VERSION 5.7 ;
  NOWIREEXTENSIONATPIN ON ;
  DIVIDERCHAR "/" ;
  BUSBITCHARS "[]" ;
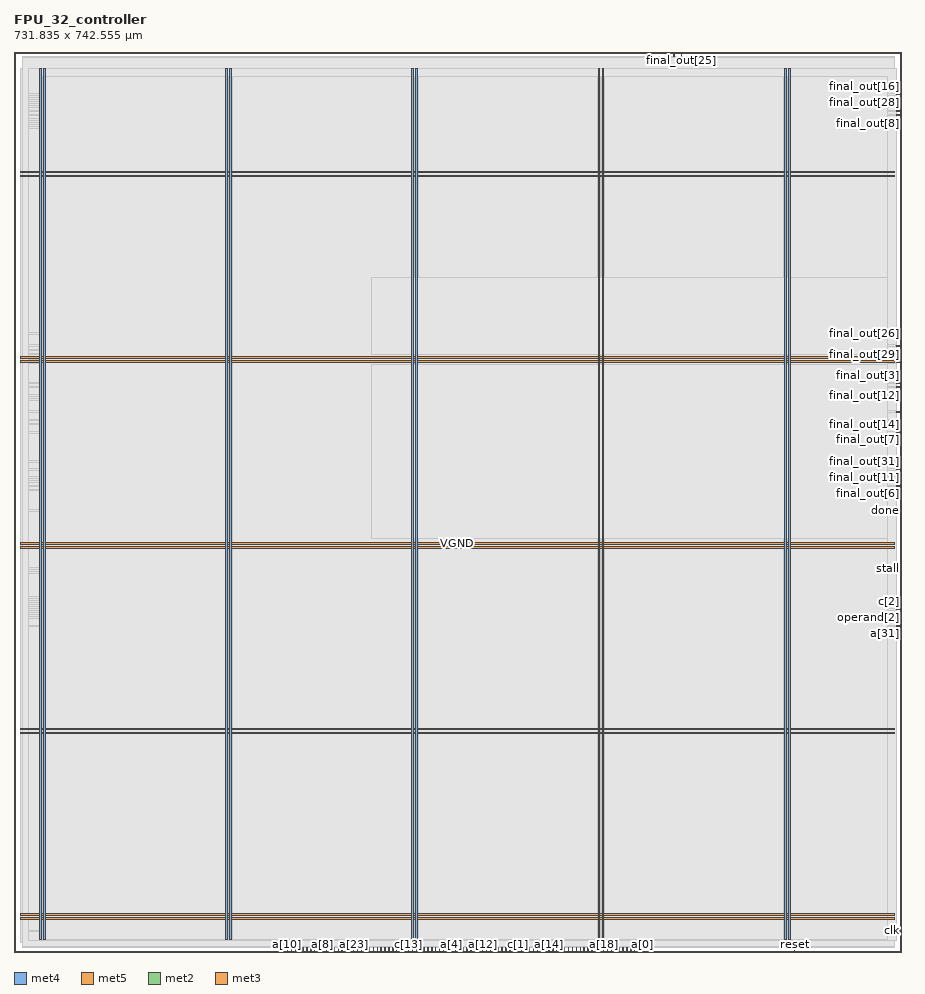
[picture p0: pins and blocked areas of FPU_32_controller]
MACRO FPU_32_controller
  CLASS BLOCK ;
  FOREIGN FPU_32_controller ;
  ORIGIN 0.000 0.000 ;
  SIZE 731.835 BY 742.555 ;
  PIN VGND
    DIRECTION INOUT ;
    USE GROUND ;
    PORT
      LAYER met4 ;
        RECT 24.340 10.640 25.940 729.200 ;
    END
    PORT
      LAYER met4 ;
        RECT 177.940 10.640 179.540 729.200 ;
    END
    PORT
      LAYER met4 ;
        RECT 331.540 10.640 333.140 729.200 ;
    END
    PORT
      LAYER met4 ;
        RECT 485.140 10.640 486.740 729.200 ;
    END
    PORT
      LAYER met4 ;
        RECT 638.740 10.640 640.340 729.200 ;
    END
    PORT
      LAYER met5 ;
        RECT 5.280 30.030 726.120 31.630 ;
    END
    PORT
      LAYER met5 ;
        RECT 5.280 183.210 726.120 184.810 ;
    END
    PORT
      LAYER met5 ;
        RECT 5.280 336.390 726.120 337.990 ;
    END
    PORT
      LAYER met5 ;
        RECT 5.280 489.570 726.120 491.170 ;
    END
    PORT
      LAYER met5 ;
        RECT 5.280 642.750 726.120 644.350 ;
    END
  END VGND
  PIN VPWR
    DIRECTION INOUT ;
    USE POWER ;
    PORT
      LAYER met4 ;
        RECT 21.040 10.640 22.640 729.200 ;
    END
    PORT
      LAYER met4 ;
        RECT 174.640 10.640 176.240 729.200 ;
    END
    PORT
      LAYER met4 ;
        RECT 328.240 10.640 329.840 729.200 ;
    END
    PORT
      LAYER met4 ;
        RECT 481.840 10.640 483.440 729.200 ;
    END
    PORT
      LAYER met4 ;
        RECT 635.440 10.640 637.040 729.200 ;
    END
    PORT
      LAYER met5 ;
        RECT 5.280 26.730 726.120 28.330 ;
    END
    PORT
      LAYER met5 ;
        RECT 5.280 179.910 726.120 181.510 ;
    END
    PORT
      LAYER met5 ;
        RECT 5.280 333.090 726.120 334.690 ;
    END
    PORT
      LAYER met5 ;
        RECT 5.280 486.270 726.120 487.870 ;
    END
    PORT
      LAYER met5 ;
        RECT 5.280 639.450 726.120 641.050 ;
    END
  END VPWR
  PIN a[0]
    DIRECTION INPUT ;
    USE SIGNAL ;
    ANTENNAGATEAREA 0.247500 ;
    PORT
      LAYER met2 ;
        RECT 518.510 0.000 518.790 4.000 ;
    END
  END a[0]
  PIN a[10]
    DIRECTION INPUT ;
    USE SIGNAL ;
    ANTENNAGATEAREA 0.159000 ;
    PORT
      LAYER met2 ;
        RECT 225.490 0.000 225.770 4.000 ;
    END
  END a[10]
  PIN a[11]
    DIRECTION INPUT ;
    USE SIGNAL ;
    ANTENNAGATEAREA 0.159000 ;
    PORT
      LAYER met2 ;
        RECT 228.710 0.000 228.990 4.000 ;
    END
  END a[11]
  PIN a[12]
    DIRECTION INPUT ;
    USE SIGNAL ;
    ANTENNAGATEAREA 0.159000 ;
    PORT
      LAYER met2 ;
        RECT 386.490 0.000 386.770 4.000 ;
    END
  END a[12]
  PIN a[13]
    DIRECTION INPUT ;
    USE SIGNAL ;
    ANTENNAGATEAREA 0.159000 ;
    PORT
      LAYER met2 ;
        RECT 389.710 0.000 389.990 4.000 ;
    END
  END a[13]
  PIN a[14]
    DIRECTION INPUT ;
    USE SIGNAL ;
    ANTENNAGATEAREA 0.213000 ;
    PORT
      LAYER met2 ;
        RECT 441.230 0.000 441.510 4.000 ;
    END
  END a[14]
  PIN a[15]
    DIRECTION INPUT ;
    USE SIGNAL ;
    ANTENNAGATEAREA 0.159000 ;
    PORT
      LAYER met2 ;
        RECT 396.150 0.000 396.430 4.000 ;
    END
  END a[15]
  PIN a[16]
    DIRECTION INPUT ;
    USE SIGNAL ;
    ANTENNAGATEAREA 0.213000 ;
    PORT
      LAYER met2 ;
        RECT 499.190 0.000 499.470 4.000 ;
    END
  END a[16]
  PIN a[17]
    DIRECTION INPUT ;
    USE SIGNAL ;
    ANTENNAGATEAREA 0.213000 ;
    PORT
      LAYER met2 ;
        RECT 508.850 0.000 509.130 4.000 ;
    END
  END a[17]
  PIN a[18]
    DIRECTION INPUT ;
    USE SIGNAL ;
    ANTENNAGATEAREA 0.213000 ;
    PORT
      LAYER met2 ;
        RECT 486.310 0.000 486.590 4.000 ;
    END
  END a[18]
  PIN a[19]
    DIRECTION INPUT ;
    USE SIGNAL ;
    ANTENNAGATEAREA 0.213000 ;
    PORT
      LAYER met2 ;
        RECT 483.090 0.000 483.370 4.000 ;
    END
  END a[19]
  PIN a[1]
    DIRECTION INPUT ;
    USE SIGNAL ;
    ANTENNAGATEAREA 0.213000 ;
    PORT
      LAYER met2 ;
        RECT 402.590 0.000 402.870 4.000 ;
    END
  END a[1]
  PIN a[20]
    DIRECTION INPUT ;
    USE SIGNAL ;
    ANTENNAGATEAREA 0.213000 ;
    PORT
      LAYER met2 ;
        RECT 476.650 0.000 476.930 4.000 ;
    END
  END a[20]
  PIN a[21]
    DIRECTION INPUT ;
    USE SIGNAL ;
    ANTENNAGATEAREA 0.213000 ;
    PORT
      LAYER met2 ;
        RECT 489.530 0.000 489.810 4.000 ;
    END
  END a[21]
  PIN a[22]
    DIRECTION INPUT ;
    USE SIGNAL ;
    ANTENNAGATEAREA 0.213000 ;
    PORT
      LAYER met2 ;
        RECT 470.210 0.000 470.490 4.000 ;
    END
  END a[22]
  PIN a[23]
    DIRECTION INPUT ;
    USE SIGNAL ;
    ANTENNAGATEAREA 0.159000 ;
    PORT
      LAYER met2 ;
        RECT 280.230 0.000 280.510 4.000 ;
    END
  END a[23]
  PIN a[24]
    DIRECTION INPUT ;
    USE SIGNAL ;
    ANTENNAGATEAREA 0.213000 ;
    PORT
      LAYER met2 ;
        RECT 463.770 0.000 464.050 4.000 ;
    END
  END a[24]
  PIN a[25]
    DIRECTION INPUT ;
    USE SIGNAL ;
    ANTENNAGATEAREA 0.213000 ;
    PORT
      LAYER met2 ;
        RECT 357.510 0.000 357.790 4.000 ;
    END
  END a[25]
  PIN a[26]
    DIRECTION INPUT ;
    USE SIGNAL ;
    ANTENNAGATEAREA 0.159000 ;
    PORT
      LAYER met2 ;
        RECT 251.250 0.000 251.530 4.000 ;
    END
  END a[26]
  PIN a[27]
    DIRECTION INPUT ;
    USE SIGNAL ;
    ANTENNAGATEAREA 0.159000 ;
    PORT
      LAYER met2 ;
        RECT 231.930 0.000 232.210 4.000 ;
    END
  END a[27]
  PIN a[28]
    DIRECTION INPUT ;
    USE SIGNAL ;
    ANTENNAGATEAREA 0.213000 ;
    PORT
      LAYER met2 ;
        RECT 460.550 0.000 460.830 4.000 ;
    END
  END a[28]
  PIN a[29]
    DIRECTION INPUT ;
    USE SIGNAL ;
    ANTENNAGATEAREA 0.213000 ;
    PORT
      LAYER met2 ;
        RECT 479.870 0.000 480.150 4.000 ;
    END
  END a[29]
  PIN a[2]
    DIRECTION INPUT ;
    USE SIGNAL ;
    ANTENNAGATEAREA 0.213000 ;
    PORT
      LAYER met2 ;
        RECT 380.050 0.000 380.330 4.000 ;
    END
  END a[2]
  PIN a[30]
    DIRECTION INPUT ;
    USE SIGNAL ;
    ANTENNAGATEAREA 0.213000 ;
    PORT
      LAYER met2 ;
        RECT 392.930 0.000 393.210 4.000 ;
    END
  END a[30]
  PIN a[31]
    DIRECTION INPUT ;
    USE SIGNAL ;
    ANTENNAGATEAREA 0.247500 ;
    PORT
      LAYER met3 ;
        RECT 727.835 268.640 731.835 269.240 ;
    END
  END a[31]
  PIN a[3]
    DIRECTION INPUT ;
    USE SIGNAL ;
    ANTENNAGATEAREA 0.213000 ;
    PORT
      LAYER met2 ;
        RECT 502.410 0.000 502.690 4.000 ;
    END
  END a[3]
  PIN a[4]
    DIRECTION INPUT ;
    USE SIGNAL ;
    ANTENNAGATEAREA 0.159000 ;
    PORT
      LAYER met2 ;
        RECT 360.730 0.000 361.010 4.000 ;
    END
  END a[4]
  PIN a[5]
    DIRECTION INPUT ;
    USE SIGNAL ;
    ANTENNAGATEAREA 0.213000 ;
    PORT
      LAYER met2 ;
        RECT 244.810 0.000 245.090 4.000 ;
    END
  END a[5]
  PIN a[6]
    DIRECTION INPUT ;
    USE SIGNAL ;
    ANTENNAGATEAREA 0.213000 ;
    PORT
      LAYER met2 ;
        RECT 235.150 0.000 235.430 4.000 ;
    END
  END a[6]
  PIN a[7]
    DIRECTION INPUT ;
    USE SIGNAL ;
    ANTENNAGATEAREA 0.213000 ;
    PORT
      LAYER met2 ;
        RECT 248.030 0.000 248.310 4.000 ;
    END
  END a[7]
  PIN a[8]
    DIRECTION INPUT ;
    USE SIGNAL ;
    ANTENNAGATEAREA 0.159000 ;
    PORT
      LAYER met2 ;
        RECT 254.470 0.000 254.750 4.000 ;
    END
  END a[8]
  PIN a[9]
    DIRECTION INPUT ;
    USE SIGNAL ;
    ANTENNAGATEAREA 0.159000 ;
    PORT
      LAYER met2 ;
        RECT 241.590 0.000 241.870 4.000 ;
    END
  END a[9]
  PIN b[0]
    DIRECTION INPUT ;
    USE SIGNAL ;
    ANTENNAGATEAREA 0.213000 ;
    PORT
      LAYER met2 ;
        RECT 457.330 0.000 457.610 4.000 ;
    END
  END b[0]
  PIN b[10]
    DIRECTION INPUT ;
    USE SIGNAL ;
    ANTENNAGATEAREA 0.126000 ;
    PORT
      LAYER met2 ;
        RECT 376.830 0.000 377.110 4.000 ;
    END
  END b[10]
  PIN b[11]
    DIRECTION INPUT ;
    USE SIGNAL ;
    ANTENNAGATEAREA 0.196500 ;
    PORT
      LAYER met2 ;
        RECT 383.270 0.000 383.550 4.000 ;
    END
  END b[11]
  PIN b[12]
    DIRECTION INPUT ;
    USE SIGNAL ;
    ANTENNAGATEAREA 0.159000 ;
    PORT
      LAYER met2 ;
        RECT 505.630 0.000 505.910 4.000 ;
    END
  END b[12]
  PIN b[13]
    DIRECTION INPUT ;
    USE SIGNAL ;
    ANTENNAGATEAREA 0.196500 ;
    PORT
      LAYER met2 ;
        RECT 409.030 0.000 409.310 4.000 ;
    END
  END b[13]
  PIN b[14]
    DIRECTION INPUT ;
    USE SIGNAL ;
    ANTENNAGATEAREA 0.196500 ;
    PORT
      LAYER met2 ;
        RECT 431.570 0.000 431.850 4.000 ;
    END
  END b[14]
  PIN b[15]
    DIRECTION INPUT ;
    USE SIGNAL ;
    ANTENNAGATEAREA 0.213000 ;
    PORT
      LAYER met2 ;
        RECT 428.350 0.000 428.630 4.000 ;
    END
  END b[15]
  PIN b[16]
    DIRECTION INPUT ;
    USE SIGNAL ;
    ANTENNAGATEAREA 0.126000 ;
    PORT
      LAYER met2 ;
        RECT 425.130 0.000 425.410 4.000 ;
    END
  END b[16]
  PIN b[17]
    DIRECTION INPUT ;
    USE SIGNAL ;
    ANTENNAGATEAREA 0.213000 ;
    PORT
      LAYER met2 ;
        RECT 444.450 0.000 444.730 4.000 ;
    END
  END b[17]
  PIN b[18]
    DIRECTION INPUT ;
    USE SIGNAL ;
    ANTENNAGATEAREA 0.159000 ;
    PORT
      LAYER met2 ;
        RECT 515.290 0.000 515.570 4.000 ;
    END
  END b[18]
  PIN b[19]
    DIRECTION INPUT ;
    USE SIGNAL ;
    ANTENNAGATEAREA 0.196500 ;
    PORT
      LAYER met2 ;
        RECT 399.370 0.000 399.650 4.000 ;
    END
  END b[19]
  PIN b[1]
    DIRECTION INPUT ;
    USE SIGNAL ;
    ANTENNAGATEAREA 0.213000 ;
    PORT
      LAYER met2 ;
        RECT 447.670 0.000 447.950 4.000 ;
    END
  END b[1]
  PIN b[20]
    DIRECTION INPUT ;
    USE SIGNAL ;
    ANTENNAGATEAREA 0.159000 ;
    PORT
      LAYER met2 ;
        RECT 466.990 0.000 467.270 4.000 ;
    END
  END b[20]
  PIN b[21]
    DIRECTION INPUT ;
    USE SIGNAL ;
    ANTENNAGATEAREA 0.213000 ;
    PORT
      LAYER met2 ;
        RECT 412.250 0.000 412.530 4.000 ;
    END
  END b[21]
  PIN b[22]
    DIRECTION INPUT ;
    USE SIGNAL ;
    ANTENNAGATEAREA 0.213000 ;
    PORT
      LAYER met2 ;
        RECT 370.390 0.000 370.670 4.000 ;
    END
  END b[22]
  PIN b[23]
    DIRECTION INPUT ;
    USE SIGNAL ;
    ANTENNAGATEAREA 0.126000 ;
    PORT
      LAYER met2 ;
        RECT 363.950 0.000 364.230 4.000 ;
    END
  END b[23]
  PIN b[24]
    DIRECTION INPUT ;
    USE SIGNAL ;
    ANTENNAGATEAREA 0.213000 ;
    PORT
      LAYER met2 ;
        RECT 238.370 0.000 238.650 4.000 ;
    END
  END b[24]
  PIN b[25]
    DIRECTION INPUT ;
    USE SIGNAL ;
    ANTENNAGATEAREA 0.213000 ;
    PORT
      LAYER met2 ;
        RECT 289.890 0.000 290.170 4.000 ;
    END
  END b[25]
  PIN b[26]
    DIRECTION INPUT ;
    USE SIGNAL ;
    ANTENNAGATEAREA 0.213000 ;
    PORT
      LAYER met2 ;
        RECT 347.850 0.000 348.130 4.000 ;
    END
  END b[26]
  PIN b[27]
    DIRECTION INPUT ;
    USE SIGNAL ;
    ANTENNAGATEAREA 0.213000 ;
    PORT
      LAYER met2 ;
        RECT 293.110 0.000 293.390 4.000 ;
    END
  END b[27]
  PIN b[28]
    DIRECTION INPUT ;
    USE SIGNAL ;
    ANTENNAGATEAREA 0.213000 ;
    PORT
      LAYER met2 ;
        RECT 341.410 0.000 341.690 4.000 ;
    END
  END b[28]
  PIN b[29]
    DIRECTION INPUT ;
    USE SIGNAL ;
    ANTENNAGATEAREA 0.213000 ;
    PORT
      LAYER met2 ;
        RECT 315.650 0.000 315.930 4.000 ;
    END
  END b[29]
  PIN b[2]
    DIRECTION INPUT ;
    USE SIGNAL ;
    ANTENNAGATEAREA 0.213000 ;
    PORT
      LAYER met2 ;
        RECT 450.890 0.000 451.170 4.000 ;
    END
  END b[2]
  PIN b[30]
    DIRECTION INPUT ;
    USE SIGNAL ;
    ANTENNAGATEAREA 0.213000 ;
    PORT
      LAYER met2 ;
        RECT 354.290 0.000 354.570 4.000 ;
    END
  END b[30]
  PIN b[31]
    DIRECTION INPUT ;
    USE SIGNAL ;
    ANTENNAGATEAREA 0.213000 ;
    PORT
      LAYER met3 ;
        RECT 727.835 292.440 731.835 293.040 ;
    END
  END b[31]
  PIN b[3]
    DIRECTION INPUT ;
    USE SIGNAL ;
    ANTENNAGATEAREA 0.213000 ;
    PORT
      LAYER met2 ;
        RECT 454.110 0.000 454.390 4.000 ;
    END
  END b[3]
  PIN b[4]
    DIRECTION INPUT ;
    USE SIGNAL ;
    ANTENNAGATEAREA 0.159000 ;
    PORT
      LAYER met2 ;
        RECT 495.970 0.000 496.250 4.000 ;
    END
  END b[4]
  PIN b[5]
    DIRECTION INPUT ;
    USE SIGNAL ;
    ANTENNAGATEAREA 0.213000 ;
    PORT
      LAYER met2 ;
        RECT 492.750 0.000 493.030 4.000 ;
    END
  END b[5]
  PIN b[6]
    DIRECTION INPUT ;
    USE SIGNAL ;
    ANTENNAGATEAREA 0.159000 ;
    PORT
      LAYER met2 ;
        RECT 473.430 0.000 473.710 4.000 ;
    END
  END b[6]
  PIN b[7]
    DIRECTION INPUT ;
    USE SIGNAL ;
    ANTENNAGATEAREA 0.196500 ;
    PORT
      LAYER met2 ;
        RECT 405.810 0.000 406.090 4.000 ;
    END
  END b[7]
  PIN b[8]
    DIRECTION INPUT ;
    USE SIGNAL ;
    ANTENNAGATEAREA 0.126000 ;
    PORT
      LAYER met2 ;
        RECT 367.170 0.000 367.450 4.000 ;
    END
  END b[8]
  PIN b[9]
    DIRECTION INPUT ;
    USE SIGNAL ;
    ANTENNAGATEAREA 0.126000 ;
    PORT
      LAYER met2 ;
        RECT 373.610 0.000 373.890 4.000 ;
    END
  END b[9]
  PIN c[0]
    DIRECTION INPUT ;
    USE SIGNAL ;
    ANTENNAGATEAREA 0.196500 ;
    PORT
      LAYER met2 ;
        RECT 434.790 0.000 435.070 4.000 ;
    END
  END c[0]
  PIN c[10]
    DIRECTION INPUT ;
    USE SIGNAL ;
    ANTENNAGATEAREA 0.196500 ;
    PORT
      LAYER met2 ;
        RECT 344.630 0.000 344.910 4.000 ;
    END
  END c[10]
  PIN c[11]
    DIRECTION INPUT ;
    USE SIGNAL ;
    ANTENNAGATEAREA 0.196500 ;
    PORT
      LAYER met2 ;
        RECT 351.070 0.000 351.350 4.000 ;
    END
  END c[11]
  PIN c[12]
    DIRECTION INPUT ;
    USE SIGNAL ;
    ANTENNAGATEAREA 0.196500 ;
    PORT
      LAYER met2 ;
        RECT 296.330 0.000 296.610 4.000 ;
    END
  END c[12]
  PIN c[13]
    DIRECTION INPUT ;
    USE SIGNAL ;
    ANTENNAGATEAREA 0.196500 ;
    PORT
      LAYER met2 ;
        RECT 325.310 0.000 325.590 4.000 ;
    END
  END c[13]
  PIN c[14]
    DIRECTION INPUT ;
    USE SIGNAL ;
    ANTENNAGATEAREA 0.196500 ;
    PORT
      LAYER met2 ;
        RECT 418.690 0.000 418.970 4.000 ;
    END
  END c[14]
  PIN c[15]
    DIRECTION INPUT ;
    USE SIGNAL ;
    ANTENNAGATEAREA 0.196500 ;
    PORT
      LAYER met2 ;
        RECT 257.690 0.000 257.970 4.000 ;
    END
  END c[15]
  PIN c[16]
    DIRECTION INPUT ;
    USE SIGNAL ;
    ANTENNAGATEAREA 0.196500 ;
    PORT
      LAYER met2 ;
        RECT 421.910 0.000 422.190 4.000 ;
    END
  END c[16]
  PIN c[17]
    DIRECTION INPUT ;
    USE SIGNAL ;
    ANTENNAGATEAREA 0.196500 ;
    PORT
      LAYER met2 ;
        RECT 322.090 0.000 322.370 4.000 ;
    END
  END c[17]
  PIN c[18]
    DIRECTION INPUT ;
    USE SIGNAL ;
    ANTENNAGATEAREA 0.196500 ;
    PORT
      LAYER met2 ;
        RECT 331.750 0.000 332.030 4.000 ;
    END
  END c[18]
  PIN c[19]
    DIRECTION INPUT ;
    USE SIGNAL ;
    ANTENNAGATEAREA 0.196500 ;
    PORT
      LAYER met2 ;
        RECT 260.910 0.000 261.190 4.000 ;
    END
  END c[19]
  PIN c[1]
    DIRECTION INPUT ;
    USE SIGNAL ;
    ANTENNAGATEAREA 0.196500 ;
    PORT
      LAYER met2 ;
        RECT 415.470 0.000 415.750 4.000 ;
    END
  END c[1]
  PIN c[20]
    DIRECTION INPUT ;
    USE SIGNAL ;
    ANTENNAGATEAREA 0.196500 ;
    PORT
      LAYER met2 ;
        RECT 512.070 0.000 512.350 4.000 ;
    END
  END c[20]
  PIN c[21]
    DIRECTION INPUT ;
    USE SIGNAL ;
    ANTENNAGATEAREA 0.196500 ;
    PORT
      LAYER met2 ;
        RECT 299.550 0.000 299.830 4.000 ;
    END
  END c[21]
  PIN c[22]
    DIRECTION INPUT ;
    USE SIGNAL ;
    ANTENNAGATEAREA 0.196500 ;
    PORT
      LAYER met2 ;
        RECT 305.990 0.000 306.270 4.000 ;
    END
  END c[22]
  PIN c[23]
    DIRECTION INPUT ;
    USE SIGNAL ;
    ANTENNAGATEAREA 0.196500 ;
    PORT
      LAYER met2 ;
        RECT 267.350 0.000 267.630 4.000 ;
    END
  END c[23]
  PIN c[24]
    DIRECTION INPUT ;
    USE SIGNAL ;
    ANTENNAGATEAREA 0.196500 ;
    PORT
      LAYER met2 ;
        RECT 273.790 0.000 274.070 4.000 ;
    END
  END c[24]
  PIN c[25]
    DIRECTION INPUT ;
    USE SIGNAL ;
    ANTENNAGATEAREA 0.196500 ;
    PORT
      LAYER met2 ;
        RECT 334.970 0.000 335.250 4.000 ;
    END
  END c[25]
  PIN c[26]
    DIRECTION INPUT ;
    USE SIGNAL ;
    ANTENNAGATEAREA 0.196500 ;
    PORT
      LAYER met2 ;
        RECT 302.770 0.000 303.050 4.000 ;
    END
  END c[26]
  PIN c[27]
    DIRECTION INPUT ;
    USE SIGNAL ;
    ANTENNAGATEAREA 0.196500 ;
    PORT
      LAYER met2 ;
        RECT 312.430 0.000 312.710 4.000 ;
    END
  END c[27]
  PIN c[28]
    DIRECTION INPUT ;
    USE SIGNAL ;
    ANTENNAGATEAREA 0.196500 ;
    PORT
      LAYER met2 ;
        RECT 283.450 0.000 283.730 4.000 ;
    END
  END c[28]
  PIN c[29]
    DIRECTION INPUT ;
    USE SIGNAL ;
    ANTENNAGATEAREA 0.196500 ;
    PORT
      LAYER met2 ;
        RECT 270.570 0.000 270.850 4.000 ;
    END
  END c[29]
  PIN c[2]
    DIRECTION INPUT ;
    USE SIGNAL ;
    ANTENNAGATEAREA 0.213000 ;
    PORT
      LAYER met3 ;
        RECT 727.835 289.040 731.835 289.640 ;
    END
  END c[2]
  PIN c[30]
    DIRECTION INPUT ;
    USE SIGNAL ;
    ANTENNAGATEAREA 0.196500 ;
    PORT
      LAYER met2 ;
        RECT 328.530 0.000 328.810 4.000 ;
    END
  END c[30]
  PIN c[31]
    DIRECTION INPUT ;
    USE SIGNAL ;
    ANTENNAGATEAREA 0.196500 ;
    PORT
      LAYER met2 ;
        RECT 338.190 0.000 338.470 4.000 ;
    END
  END c[31]
  PIN c[3]
    DIRECTION INPUT ;
    USE SIGNAL ;
    ANTENNAGATEAREA 0.196500 ;
    PORT
      LAYER met2 ;
        RECT 438.010 0.000 438.290 4.000 ;
    END
  END c[3]
  PIN c[4]
    DIRECTION INPUT ;
    USE SIGNAL ;
    ANTENNAGATEAREA 0.196500 ;
    PORT
      LAYER met2 ;
        RECT 286.670 0.000 286.950 4.000 ;
    END
  END c[4]
  PIN c[5]
    DIRECTION INPUT ;
    USE SIGNAL ;
    ANTENNAGATEAREA 0.213000 ;
    PORT
      LAYER met3 ;
        RECT 727.835 312.840 731.835 313.440 ;
    END
  END c[5]
  PIN c[6]
    DIRECTION INPUT ;
    USE SIGNAL ;
    ANTENNAGATEAREA 0.196500 ;
    PORT
      LAYER met2 ;
        RECT 264.130 0.000 264.410 4.000 ;
    END
  END c[6]
  PIN c[7]
    DIRECTION INPUT ;
    USE SIGNAL ;
    ANTENNAGATEAREA 0.196500 ;
    PORT
      LAYER met2 ;
        RECT 309.210 0.000 309.490 4.000 ;
    END
  END c[7]
  PIN c[8]
    DIRECTION INPUT ;
    USE SIGNAL ;
    ANTENNAGATEAREA 0.196500 ;
    PORT
      LAYER met2 ;
        RECT 318.870 0.000 319.150 4.000 ;
    END
  END c[8]
  PIN c[9]
    DIRECTION INPUT ;
    USE SIGNAL ;
    ANTENNAGATEAREA 0.196500 ;
    PORT
      LAYER met2 ;
        RECT 277.010 0.000 277.290 4.000 ;
    END
  END c[9]
  PIN clk
    DIRECTION INPUT ;
    USE SIGNAL ;
    ANTENNAGATEAREA 1.286700 ;
    ANTENNADIFFAREA 0.434700 ;
    PORT
      LAYER met3 ;
        RECT 727.835 17.040 731.835 17.640 ;
    END
  END clk
  PIN done
    DIRECTION OUTPUT ;
    USE SIGNAL ;
    ANTENNADIFFAREA 0.445500 ;
    PORT
      LAYER met3 ;
        RECT 727.835 363.840 731.835 364.440 ;
    END
  END done
  PIN final_out[0]
    DIRECTION OUTPUT ;
    USE SIGNAL ;
    ANTENNADIFFAREA 0.445500 ;
    PORT
      LAYER met3 ;
        RECT 727.835 380.840 731.835 381.440 ;
    END
  END final_out[0]
  PIN final_out[10]
    DIRECTION OUTPUT ;
    USE SIGNAL ;
    ANTENNADIFFAREA 0.445500 ;
    PORT
      LAYER met3 ;
        RECT 727.835 489.640 731.835 490.240 ;
    END
  END final_out[10]
  PIN final_out[11]
    DIRECTION OUTPUT ;
    USE SIGNAL ;
    ANTENNADIFFAREA 0.445500 ;
    PORT
      LAYER met3 ;
        RECT 727.835 391.040 731.835 391.640 ;
    END
  END final_out[11]
  PIN final_out[12]
    DIRECTION OUTPUT ;
    USE SIGNAL ;
    ANTENNADIFFAREA 0.445500 ;
    PORT
      LAYER met3 ;
        RECT 727.835 459.040 731.835 459.640 ;
    END
  END final_out[12]
  PIN final_out[13]
    DIRECTION OUTPUT ;
    USE SIGNAL ;
    ANTENNADIFFAREA 0.445500 ;
    PORT
      LAYER met3 ;
        RECT 727.835 455.640 731.835 456.240 ;
    END
  END final_out[13]
  PIN final_out[14]
    DIRECTION OUTPUT ;
    USE SIGNAL ;
    ANTENNADIFFAREA 0.445500 ;
    PORT
      LAYER met3 ;
        RECT 727.835 435.240 731.835 435.840 ;
    END
  END final_out[14]
  PIN final_out[15]
    DIRECTION OUTPUT ;
    USE SIGNAL ;
    ANTENNADIFFAREA 0.445500 ;
    PORT
      LAYER met3 ;
        RECT 727.835 496.440 731.835 497.040 ;
    END
  END final_out[15]
  PIN final_out[16]
    DIRECTION OUTPUT ;
    USE SIGNAL ;
    ANTENNADIFFAREA 0.445500 ;
    PORT
      LAYER met3 ;
        RECT 727.835 707.240 731.835 707.840 ;
    END
  END final_out[16]
  PIN final_out[17]
    DIRECTION OUTPUT ;
    USE SIGNAL ;
    ANTENNADIFFAREA 0.445500 ;
    PORT
      LAYER met3 ;
        RECT 727.835 693.640 731.835 694.240 ;
    END
  END final_out[17]
  PIN final_out[18]
    DIRECTION OUTPUT ;
    USE SIGNAL ;
    ANTENNADIFFAREA 0.445500 ;
    PORT
      LAYER met3 ;
        RECT 727.835 680.040 731.835 680.640 ;
    END
  END final_out[18]
  PIN final_out[19]
    DIRECTION OUTPUT ;
    USE SIGNAL ;
    ANTENNADIFFAREA 0.445500 ;
    PORT
      LAYER met3 ;
        RECT 727.835 690.240 731.835 690.840 ;
    END
  END final_out[19]
  PIN final_out[1]
    DIRECTION OUTPUT ;
    USE SIGNAL ;
    ANTENNADIFFAREA 0.445500 ;
    PORT
      LAYER met3 ;
        RECT 727.835 387.640 731.835 388.240 ;
    END
  END final_out[1]
  PIN final_out[20]
    DIRECTION OUTPUT ;
    USE SIGNAL ;
    ANTENNADIFFAREA 0.445500 ;
    PORT
      LAYER met3 ;
        RECT 727.835 697.040 731.835 697.640 ;
    END
  END final_out[20]
  PIN final_out[21]
    DIRECTION OUTPUT ;
    USE SIGNAL ;
    ANTENNADIFFAREA 0.445500 ;
    PORT
      LAYER met3 ;
        RECT 727.835 703.840 731.835 704.440 ;
    END
  END final_out[21]
  PIN final_out[22]
    DIRECTION OUTPUT ;
    USE SIGNAL ;
    ANTENNADIFFAREA 0.445500 ;
    PORT
      LAYER met3 ;
        RECT 727.835 686.840 731.835 687.440 ;
    END
  END final_out[22]
  PIN final_out[23]
    DIRECTION OUTPUT ;
    USE SIGNAL ;
    ANTENNADIFFAREA 0.445500 ;
    PORT
      LAYER met3 ;
        RECT 727.835 445.440 731.835 446.040 ;
    END
  END final_out[23]
  PIN final_out[24]
    DIRECTION OUTPUT ;
    USE SIGNAL ;
    ANTENNADIFFAREA 0.445500 ;
    PORT
      LAYER met2 ;
        RECT 541.050 738.555 541.330 742.555 ;
    END
  END final_out[24]
  PIN final_out[25]
    DIRECTION OUTPUT ;
    USE SIGNAL ;
    ANTENNADIFFAREA 0.445500 ;
    PORT
      LAYER met2 ;
        RECT 550.710 738.555 550.990 742.555 ;
    END
  END final_out[25]
  PIN final_out[26]
    DIRECTION OUTPUT ;
    USE SIGNAL ;
    ANTENNADIFFAREA 0.445500 ;
    PORT
      LAYER met3 ;
        RECT 727.835 510.040 731.835 510.640 ;
    END
  END final_out[26]
  PIN final_out[27]
    DIRECTION OUTPUT ;
    USE SIGNAL ;
    ANTENNADIFFAREA 0.445500 ;
    PORT
      LAYER met2 ;
        RECT 544.270 738.555 544.550 742.555 ;
    END
  END final_out[27]
  PIN final_out[28]
    DIRECTION OUTPUT ;
    USE SIGNAL ;
    ANTENNADIFFAREA 0.445500 ;
    PORT
      LAYER met3 ;
        RECT 727.835 700.440 731.835 701.040 ;
    END
  END final_out[28]
  PIN final_out[29]
    DIRECTION OUTPUT ;
    USE SIGNAL ;
    ANTENNADIFFAREA 0.445500 ;
    PORT
      LAYER met3 ;
        RECT 727.835 493.040 731.835 493.640 ;
    END
  END final_out[29]
  PIN final_out[2]
    DIRECTION OUTPUT ;
    USE SIGNAL ;
    ANTENNADIFFAREA 0.445500 ;
    PORT
      LAYER met3 ;
        RECT 727.835 438.640 731.835 439.240 ;
    END
  END final_out[2]
  PIN final_out[30]
    DIRECTION OUTPUT ;
    USE SIGNAL ;
    ANTENNADIFFAREA 0.445500 ;
    PORT
      LAYER met3 ;
        RECT 727.835 465.840 731.835 466.440 ;
    END
  END final_out[30]
  PIN final_out[31]
    DIRECTION OUTPUT ;
    USE SIGNAL ;
    ANTENNADIFFAREA 0.445500 ;
    PORT
      LAYER met3 ;
        RECT 727.835 404.640 731.835 405.240 ;
    END
  END final_out[31]
  PIN final_out[3]
    DIRECTION OUTPUT ;
    USE SIGNAL ;
    ANTENNADIFFAREA 0.445500 ;
    PORT
      LAYER met3 ;
        RECT 727.835 469.240 731.835 469.840 ;
    END
  END final_out[3]
  PIN final_out[4]
    DIRECTION OUTPUT ;
    USE SIGNAL ;
    ANTENNADIFFAREA 0.445500 ;
    PORT
      LAYER met3 ;
        RECT 727.835 499.840 731.835 500.440 ;
    END
  END final_out[4]
  PIN final_out[5]
    DIRECTION OUTPUT ;
    USE SIGNAL ;
    ANTENNADIFFAREA 0.445500 ;
    PORT
      LAYER met3 ;
        RECT 727.835 397.840 731.835 398.440 ;
    END
  END final_out[5]
  PIN final_out[6]
    DIRECTION OUTPUT ;
    USE SIGNAL ;
    ANTENNADIFFAREA 0.445500 ;
    PORT
      LAYER met3 ;
        RECT 727.835 384.240 731.835 384.840 ;
    END
  END final_out[6]
  PIN final_out[7]
    DIRECTION OUTPUT ;
    USE SIGNAL ;
    ANTENNADIFFAREA 0.445500 ;
    PORT
      LAYER met3 ;
        RECT 727.835 428.440 731.835 429.040 ;
    END
  END final_out[7]
  PIN final_out[8]
    DIRECTION OUTPUT ;
    USE SIGNAL ;
    ANTENNADIFFAREA 0.445500 ;
    PORT
      LAYER met3 ;
        RECT 727.835 683.440 731.835 684.040 ;
    END
  END final_out[8]
  PIN final_out[9]
    DIRECTION OUTPUT ;
    USE SIGNAL ;
    ANTENNADIFFAREA 0.445500 ;
    PORT
      LAYER met3 ;
        RECT 727.835 486.240 731.835 486.840 ;
    END
  END final_out[9]
  PIN operand[0]
    DIRECTION INPUT ;
    USE SIGNAL ;
    ANTENNAGATEAREA 0.247500 ;
    PORT
      LAYER met3 ;
        RECT 727.835 275.440 731.835 276.040 ;
    END
  END operand[0]
  PIN operand[1]
    DIRECTION INPUT ;
    USE SIGNAL ;
    ANTENNAGATEAREA 0.247500 ;
    PORT
      LAYER met3 ;
        RECT 727.835 278.840 731.835 279.440 ;
    END
  END operand[1]
  PIN operand[2]
    DIRECTION INPUT ;
    USE SIGNAL ;
    ANTENNAGATEAREA 0.247500 ;
    PORT
      LAYER met3 ;
        RECT 727.835 282.240 731.835 282.840 ;
    END
  END operand[2]
  PIN operand[3]
    DIRECTION INPUT ;
    USE SIGNAL ;
    ANTENNAGATEAREA 0.426000 ;
    PORT
      LAYER met3 ;
        RECT 727.835 285.640 731.835 286.240 ;
    END
  END operand[3]
  PIN reset
    DIRECTION INPUT ;
    USE SIGNAL ;
    ANTENNAGATEAREA 0.159000 ;
    PORT
      LAYER met2 ;
        RECT 644.090 0.000 644.370 4.000 ;
    END
  END reset
  PIN stall
    DIRECTION OUTPUT ;
    USE SIGNAL ;
    ANTENNADIFFAREA 0.445500 ;
    PORT
      LAYER met3 ;
        RECT 727.835 316.240 731.835 316.840 ;
    END
  END stall
  OBS
      LAYER nwell ;
        RECT 5.330 10.795 726.070 729.045 ;
      LAYER li1 ;
        RECT 5.520 10.795 725.880 729.045 ;
      LAYER met1 ;
        RECT 5.520 7.860 726.730 729.200 ;
      LAYER met2 ;
        RECT 7.000 738.275 540.770 738.555 ;
        RECT 541.610 738.275 543.990 738.555 ;
        RECT 544.830 738.275 550.430 738.555 ;
        RECT 551.270 738.275 726.710 738.555 ;
        RECT 7.000 4.280 726.710 738.275 ;
        RECT 7.000 3.670 225.210 4.280 ;
        RECT 226.050 3.670 228.430 4.280 ;
        RECT 229.270 3.670 231.650 4.280 ;
        RECT 232.490 3.670 234.870 4.280 ;
        RECT 235.710 3.670 238.090 4.280 ;
        RECT 238.930 3.670 241.310 4.280 ;
        RECT 242.150 3.670 244.530 4.280 ;
        RECT 245.370 3.670 247.750 4.280 ;
        RECT 248.590 3.670 250.970 4.280 ;
        RECT 251.810 3.670 254.190 4.280 ;
        RECT 255.030 3.670 257.410 4.280 ;
        RECT 258.250 3.670 260.630 4.280 ;
        RECT 261.470 3.670 263.850 4.280 ;
        RECT 264.690 3.670 267.070 4.280 ;
        RECT 267.910 3.670 270.290 4.280 ;
        RECT 271.130 3.670 273.510 4.280 ;
        RECT 274.350 3.670 276.730 4.280 ;
        RECT 277.570 3.670 279.950 4.280 ;
        RECT 280.790 3.670 283.170 4.280 ;
        RECT 284.010 3.670 286.390 4.280 ;
        RECT 287.230 3.670 289.610 4.280 ;
        RECT 290.450 3.670 292.830 4.280 ;
        RECT 293.670 3.670 296.050 4.280 ;
        RECT 296.890 3.670 299.270 4.280 ;
        RECT 300.110 3.670 302.490 4.280 ;
        RECT 303.330 3.670 305.710 4.280 ;
        RECT 306.550 3.670 308.930 4.280 ;
        RECT 309.770 3.670 312.150 4.280 ;
        RECT 312.990 3.670 315.370 4.280 ;
        RECT 316.210 3.670 318.590 4.280 ;
        RECT 319.430 3.670 321.810 4.280 ;
        RECT 322.650 3.670 325.030 4.280 ;
        RECT 325.870 3.670 328.250 4.280 ;
        RECT 329.090 3.670 331.470 4.280 ;
        RECT 332.310 3.670 334.690 4.280 ;
        RECT 335.530 3.670 337.910 4.280 ;
        RECT 338.750 3.670 341.130 4.280 ;
        RECT 341.970 3.670 344.350 4.280 ;
        RECT 345.190 3.670 347.570 4.280 ;
        RECT 348.410 3.670 350.790 4.280 ;
        RECT 351.630 3.670 354.010 4.280 ;
        RECT 354.850 3.670 357.230 4.280 ;
        RECT 358.070 3.670 360.450 4.280 ;
        RECT 361.290 3.670 363.670 4.280 ;
        RECT 364.510 3.670 366.890 4.280 ;
        RECT 367.730 3.670 370.110 4.280 ;
        RECT 370.950 3.670 373.330 4.280 ;
        RECT 374.170 3.670 376.550 4.280 ;
        RECT 377.390 3.670 379.770 4.280 ;
        RECT 380.610 3.670 382.990 4.280 ;
        RECT 383.830 3.670 386.210 4.280 ;
        RECT 387.050 3.670 389.430 4.280 ;
        RECT 390.270 3.670 392.650 4.280 ;
        RECT 393.490 3.670 395.870 4.280 ;
        RECT 396.710 3.670 399.090 4.280 ;
        RECT 399.930 3.670 402.310 4.280 ;
        RECT 403.150 3.670 405.530 4.280 ;
        RECT 406.370 3.670 408.750 4.280 ;
        RECT 409.590 3.670 411.970 4.280 ;
        RECT 412.810 3.670 415.190 4.280 ;
        RECT 416.030 3.670 418.410 4.280 ;
        RECT 419.250 3.670 421.630 4.280 ;
        RECT 422.470 3.670 424.850 4.280 ;
        RECT 425.690 3.670 428.070 4.280 ;
        RECT 428.910 3.670 431.290 4.280 ;
        RECT 432.130 3.670 434.510 4.280 ;
        RECT 435.350 3.670 437.730 4.280 ;
        RECT 438.570 3.670 440.950 4.280 ;
        RECT 441.790 3.670 444.170 4.280 ;
        RECT 445.010 3.670 447.390 4.280 ;
        RECT 448.230 3.670 450.610 4.280 ;
        RECT 451.450 3.670 453.830 4.280 ;
        RECT 454.670 3.670 457.050 4.280 ;
        RECT 457.890 3.670 460.270 4.280 ;
        RECT 461.110 3.670 463.490 4.280 ;
        RECT 464.330 3.670 466.710 4.280 ;
        RECT 467.550 3.670 469.930 4.280 ;
        RECT 470.770 3.670 473.150 4.280 ;
        RECT 473.990 3.670 476.370 4.280 ;
        RECT 477.210 3.670 479.590 4.280 ;
        RECT 480.430 3.670 482.810 4.280 ;
        RECT 483.650 3.670 486.030 4.280 ;
        RECT 486.870 3.670 489.250 4.280 ;
        RECT 490.090 3.670 492.470 4.280 ;
        RECT 493.310 3.670 495.690 4.280 ;
        RECT 496.530 3.670 498.910 4.280 ;
        RECT 499.750 3.670 502.130 4.280 ;
        RECT 502.970 3.670 505.350 4.280 ;
        RECT 506.190 3.670 508.570 4.280 ;
        RECT 509.410 3.670 511.790 4.280 ;
        RECT 512.630 3.670 515.010 4.280 ;
        RECT 515.850 3.670 518.230 4.280 ;
        RECT 519.070 3.670 643.810 4.280 ;
        RECT 644.650 3.670 726.710 4.280 ;
      LAYER met3 ;
        RECT 12.025 708.240 727.835 729.125 ;
        RECT 12.025 706.840 727.435 708.240 ;
        RECT 12.025 704.840 727.835 706.840 ;
        RECT 12.025 703.440 727.435 704.840 ;
        RECT 12.025 701.440 727.835 703.440 ;
        RECT 12.025 700.040 727.435 701.440 ;
        RECT 12.025 698.040 727.835 700.040 ;
        RECT 12.025 696.640 727.435 698.040 ;
        RECT 12.025 694.640 727.835 696.640 ;
        RECT 12.025 693.240 727.435 694.640 ;
        RECT 12.025 691.240 727.835 693.240 ;
        RECT 12.025 689.840 727.435 691.240 ;
        RECT 12.025 687.840 727.835 689.840 ;
        RECT 12.025 686.440 727.435 687.840 ;
        RECT 12.025 684.440 727.835 686.440 ;
        RECT 12.025 683.040 727.435 684.440 ;
        RECT 12.025 681.040 727.835 683.040 ;
        RECT 12.025 679.640 727.435 681.040 ;
        RECT 12.025 511.040 727.835 679.640 ;
        RECT 12.025 509.640 727.435 511.040 ;
        RECT 12.025 500.840 727.835 509.640 ;
        RECT 12.025 499.440 727.435 500.840 ;
        RECT 12.025 497.440 727.835 499.440 ;
        RECT 12.025 496.040 727.435 497.440 ;
        RECT 12.025 494.040 727.835 496.040 ;
        RECT 12.025 492.640 727.435 494.040 ;
        RECT 12.025 490.640 727.835 492.640 ;
        RECT 12.025 489.240 727.435 490.640 ;
        RECT 12.025 487.240 727.835 489.240 ;
        RECT 12.025 485.840 727.435 487.240 ;
        RECT 12.025 470.240 727.835 485.840 ;
        RECT 12.025 468.840 727.435 470.240 ;
        RECT 12.025 466.840 727.835 468.840 ;
        RECT 12.025 465.440 727.435 466.840 ;
        RECT 12.025 460.040 727.835 465.440 ;
        RECT 12.025 458.640 727.435 460.040 ;
        RECT 12.025 456.640 727.835 458.640 ;
        RECT 12.025 455.240 727.435 456.640 ;
        RECT 12.025 446.440 727.835 455.240 ;
        RECT 12.025 445.040 727.435 446.440 ;
        RECT 12.025 439.640 727.835 445.040 ;
        RECT 12.025 438.240 727.435 439.640 ;
        RECT 12.025 436.240 727.835 438.240 ;
        RECT 12.025 434.840 727.435 436.240 ;
        RECT 12.025 429.440 727.835 434.840 ;
        RECT 12.025 428.040 727.435 429.440 ;
        RECT 12.025 405.640 727.835 428.040 ;
        RECT 12.025 404.240 727.435 405.640 ;
        RECT 12.025 398.840 727.835 404.240 ;
        RECT 12.025 397.440 727.435 398.840 ;
        RECT 12.025 392.040 727.835 397.440 ;
        RECT 12.025 390.640 727.435 392.040 ;
        RECT 12.025 388.640 727.835 390.640 ;
        RECT 12.025 387.240 727.435 388.640 ;
        RECT 12.025 385.240 727.835 387.240 ;
        RECT 12.025 383.840 727.435 385.240 ;
        RECT 12.025 381.840 727.835 383.840 ;
        RECT 12.025 380.440 727.435 381.840 ;
        RECT 12.025 364.840 727.835 380.440 ;
        RECT 12.025 363.440 727.435 364.840 ;
        RECT 12.025 317.240 727.835 363.440 ;
        RECT 12.025 315.840 727.435 317.240 ;
        RECT 12.025 313.840 727.835 315.840 ;
        RECT 12.025 312.440 727.435 313.840 ;
        RECT 12.025 293.440 727.835 312.440 ;
        RECT 12.025 292.040 727.435 293.440 ;
        RECT 12.025 290.040 727.835 292.040 ;
        RECT 12.025 288.640 727.435 290.040 ;
        RECT 12.025 286.640 727.835 288.640 ;
        RECT 12.025 285.240 727.435 286.640 ;
        RECT 12.025 283.240 727.835 285.240 ;
        RECT 12.025 281.840 727.435 283.240 ;
        RECT 12.025 279.840 727.835 281.840 ;
        RECT 12.025 278.440 727.435 279.840 ;
        RECT 12.025 276.440 727.835 278.440 ;
        RECT 12.025 275.040 727.435 276.440 ;
        RECT 12.025 269.640 727.835 275.040 ;
        RECT 12.025 268.240 727.435 269.640 ;
        RECT 12.025 18.040 727.835 268.240 ;
        RECT 12.025 16.640 727.435 18.040 ;
        RECT 12.025 9.695 727.835 16.640 ;
      LAYER met4 ;
        RECT 23.295 10.240 23.940 721.985 ;
        RECT 26.340 10.240 174.240 721.985 ;
        RECT 176.640 10.240 177.540 721.985 ;
        RECT 179.940 10.240 327.840 721.985 ;
        RECT 330.240 10.240 331.140 721.985 ;
        RECT 333.540 10.240 481.440 721.985 ;
        RECT 483.840 10.240 484.740 721.985 ;
        RECT 487.140 10.240 635.040 721.985 ;
        RECT 637.440 10.240 638.340 721.985 ;
        RECT 640.740 10.240 720.490 721.985 ;
        RECT 23.295 9.695 720.490 10.240 ;
      LAYER met5 ;
        RECT 294.980 492.770 720.700 556.700 ;
        RECT 294.980 340.900 720.700 484.670 ;
  END
END FPU_32_controller
END LIBRARY

